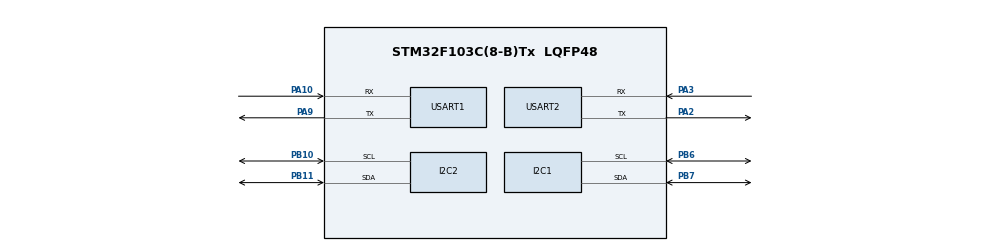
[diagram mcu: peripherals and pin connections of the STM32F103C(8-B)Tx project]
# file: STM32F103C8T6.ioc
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Mcu.Family=STM32F1
Mcu.Name=STM32F103C(8-B)Tx
Mcu.Package=LQFP48
NVIC.PriorityGroup=NVIC_PRIORITYGROUP_4
NVIC.USART2_IRQn=true\:5\:0\:true\:false\:true\:true\:true\:true
PA10.Mode=Asynchronous
PA10.Signal=USART1_RX
PA13.Mode=Serial_Wire
PA13.Signal=SYS_JTMS-SWDIO
PA14.Mode=Serial_Wire
PA14.Signal=SYS_JTCK-SWCLK
PA2.Mode=Asynchronous
PA2.Signal=USART2_TX
PA3.Mode=Asynchronous
PA3.Signal=USART2_RX
PA9.Mode=Asynchronous
PA9.Signal=USART1_TX
PB10.Mode=I2C
PB10.Signal=I2C2_SCL
PB11.Mode=I2C
PB11.Signal=I2C2_SDA
PB6.Mode=I2C
PB6.Signal=I2C1_SCL
PB7.Mode=I2C
PB7.Signal=I2C1_SDA
ProjectManager.HeapSize=0x200
ProjectManager.StackSize=0x400
ProjectManager.TargetToolchain=CMake
RCC.APB1Freq_Value=8000000
RCC.APB2Freq_Value=8000000
USART1.VirtualMode=VM_ASYNC
USART2.VirtualMode=VM_ASYNC
board=custom

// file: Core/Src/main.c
/* USER CODE BEGIN Header */
/**
  ******************************************************************************
  * @file           : main.c
  * @brief          : Main program body
  ******************************************************************************
  * @attention
  *
  * Copyright (c) 2026 STMicroelectronics.
  * All rights reserved.
  *
  * This software is licensed under terms that can be found in the LICENSE file
  * in the root directory of this software component.
  * If no LICENSE file comes with this software, it is provided AS-IS.
  *
  ******************************************************************************
  */
/* USER CODE END Header */
#include "main.h"
#include "i2c.h"
#include "usart.h"
#include "gpio.h"

/* USER CODE BEGIN Includes */
#include "app_lps22hb.h"    // I2C1 上的 LPS22HB 气压应用接口。
#include "app_ms5837.h"     // I2C2 上的 MS5837-02BA 水压应用接口。
#include "app_node_link.h"  // 从节点板间通信接口。
/* USER CODE END Includes */

void SystemClock_Config(void);

int main(void)
{

  /* MCU Configuration--------------------------------------------------------*/

  /* Reset of all peripherals, Initializes the Flash interface and the Systick. */
  HAL_Init();

  /* Configure the system clock */
  SystemClock_Config();

  /* Initialize all configured peripherals */
  MX_GPIO_Init();
  MX_I2C1_Init();
  MX_I2C2_Init();
  MX_USART1_UART_Init();
  MX_USART2_UART_Init();
  /* USER CODE BEGIN 2 */
  app_lps22hb_init();       // 初始化 I2C1 上的 LPS22HB。
  app_ms5837_init();        // 初始化 I2C2 上的 MS5837-02BA。
  app_node_link_init(3U);   // 在 USART2 启动节点 3 通信监听。
  /* USER CODE END 2 */

  /* Infinite loop */
  while (1)
  {

    /* USER CODE BEGIN 3 */
    app_node_link_run();  // 响应 Hub 发来的 PING / GET 请求。
    app_lps22hb_run();    // 按周期采样 LPS22HB 并更新第一槽。
    app_node_link_run();  // 处理前段事务期间到达的串口请求。
    app_ms5837_run();     // 非阻塞推进 MS5837-02BA 采样并更新第二槽。
  }
  /* USER CODE END 3 */
}

void SystemClock_Config(void)
{
  RCC_OscInitTypeDef RCC_OscInitStruct = {0};
  RCC_ClkInitTypeDef RCC_ClkInitStruct = {0};

  /** Initializes the RCC Oscillators according to the specified parameters
  * in the RCC_OscInitTypeDef structure.
  */
  RCC_OscInitStruct.OscillatorType = RCC_OSCILLATORTYPE_HSE;
  RCC_OscInitStruct.HSEState = RCC_HSE_ON;
  RCC_OscInitStruct.HSEPredivValue = RCC_HSE_PREDIV_DIV1;
  RCC_OscInitStruct.PLL.PLLState = RCC_PLL_ON;
  RCC_OscInitStruct.PLL.PLLSource = RCC_PLLSOURCE_HSE;
  RCC_OscInitStruct.PLL.PLLMUL = RCC_PLL_MUL9;
  if (HAL_RCC_OscConfig(&RCC_OscInitStruct) != HAL_OK)
  {
    Error_Handler();
  }

  /** Initializes the CPU, AHB and APB buses clocks
  */
  RCC_ClkInitStruct.ClockType = RCC_CLOCKTYPE_HCLK|RCC_CLOCKTYPE_SYSCLK
                              |RCC_CLOCKTYPE_PCLK1|RCC_CLOCKTYPE_PCLK2;
  RCC_ClkInitStruct.SYSCLKSource = RCC_SYSCLKSOURCE_PLLCLK;
  RCC_ClkInitStruct.AHBCLKDivider = RCC_SYSCLK_DIV1;
  RCC_ClkInitStruct.APB1CLKDivider = RCC_HCLK_DIV2;
  RCC_ClkInitStruct.APB2CLKDivider = RCC_HCLK_DIV1;

  if (HAL_RCC_ClockConfig(&RCC_ClkInitStruct, FLASH_LATENCY_2) != HAL_OK)
  {
    Error_Handler();
  }
}

void Error_Handler(void)
{
  __disable_irq();
  while (1)
  {
  }
}
